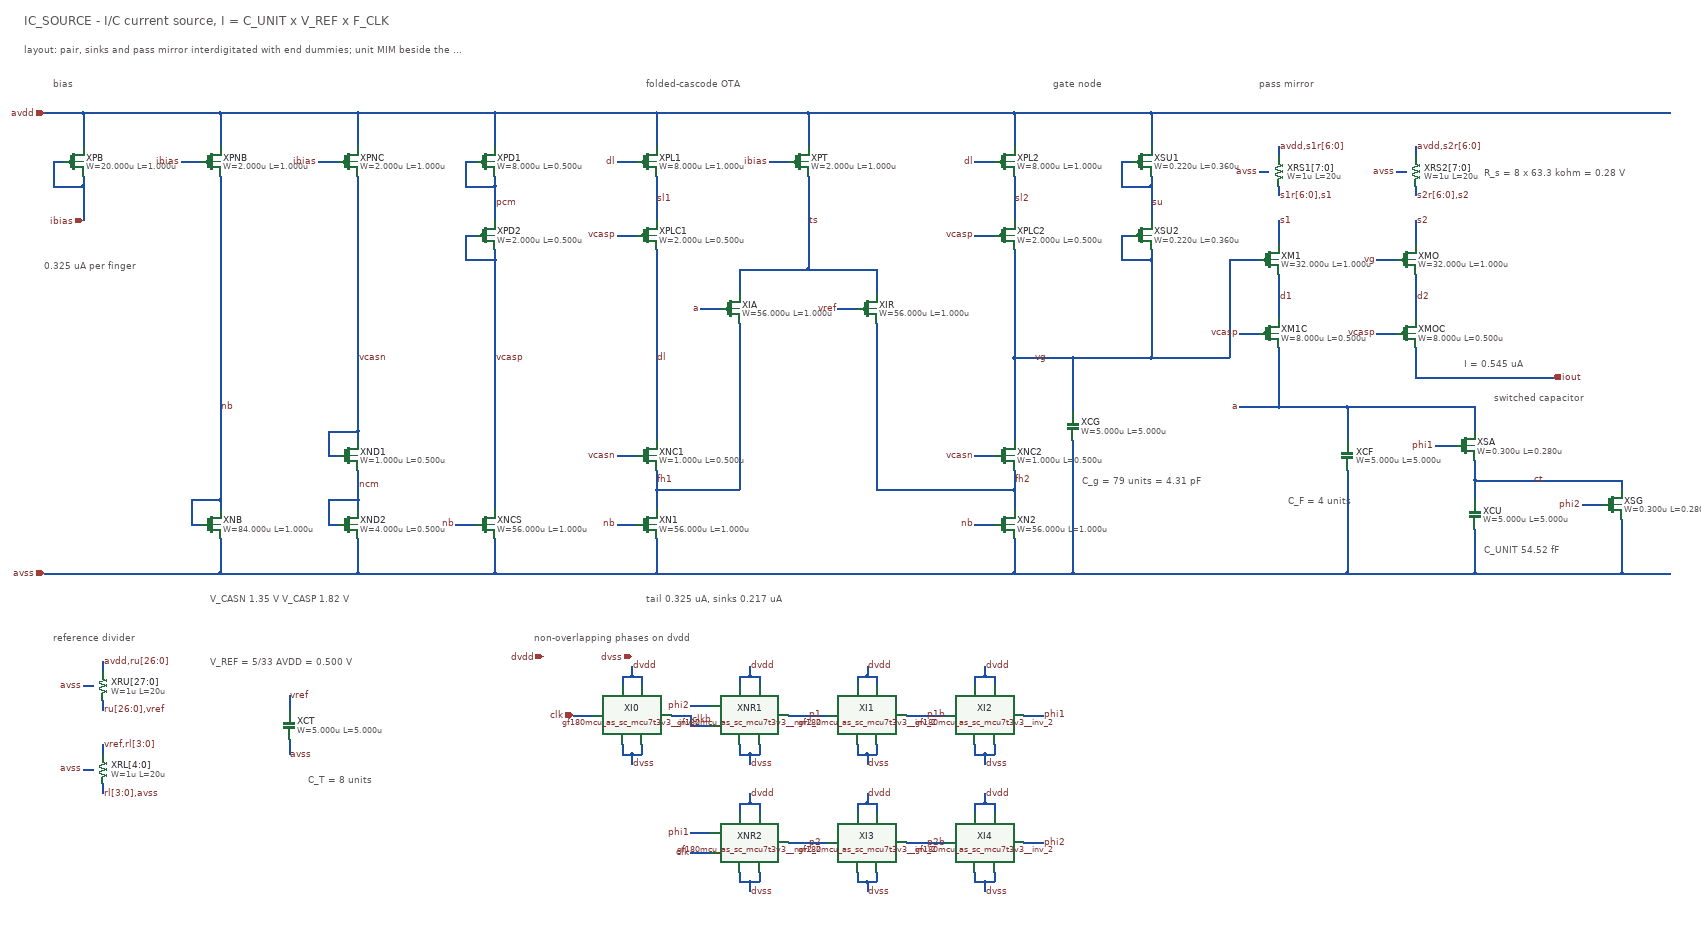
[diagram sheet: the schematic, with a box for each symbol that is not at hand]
v {xschem version=3.4.8RC file_version=1.2}
G {}
K {}
V {}
S {}
E {}
N 100 -1400 180 -1400 {}
N 100 -460 460 -460 {}
N 120 -1300 120 -1250 {}
N 120 -1300 140 -1300 {}
N 120 -1250 180 -1250 {}
N 180 -1400 180 -1330 {}
N 180 -1400 460 -1400 {}
N 180 -1270 180 -1250 {}
N 180 -1250 180 -1180 {}
N 180 -230 200 -230 {}
N 180 -60 200 -60 {}
N 220 -280 220 -260 {}
N 220 -200 220 -180 {}
N 220 -110 220 -90 {}
N 220 -30 220 -10 {}
N 380 -1300 420 -1300 {}
N 400 -610 400 -560 {}
N 400 -610 460 -610 {}
N 400 -560 420 -560 {}
N 460 -1400 460 -1330 {}
N 460 -1400 740 -1400 {}
N 460 -1270 460 -800 {}
N 460 -800 460 -610 {}
N 460 -610 460 -590 {}
N 460 -530 460 -460 {}
N 460 -460 740 -460 {}
N 600 -210 600 -180 {}
N 600 -120 600 -90 {}
N 660 -1300 700 -1300 {}
N 680 -750 680 -700 {}
N 680 -750 740 -750 {}
N 680 -700 700 -700 {}
N 680 -610 680 -560 {}
N 680 -610 740 -610 {}
N 680 -560 700 -560 {}
N 740 -1400 740 -1330 {}
N 740 -1400 1020 -1400 {}
N 740 -1270 740 -900 {}
N 740 -900 740 -750 {}
N 740 -750 740 -730 {}
N 740 -670 740 -640 {}
N 740 -640 740 -610 {}
N 740 -610 740 -590 {}
N 740 -530 740 -460 {}
N 740 -460 1020 -460 {}
N 940 -560 980 -560 {}
N 960 -1300 960 -1250 {}
N 960 -1300 980 -1300 {}
N 960 -1250 1020 -1250 {}
N 960 -1150 960 -1100 {}
N 960 -1150 980 -1150 {}
N 960 -1100 1020 -1100 {}
N 1020 -1400 1020 -1330 {}
N 1020 -1400 1350 -1400 {}
N 1020 -1270 1020 -1250 {}
N 1020 -1250 1020 -1215 {}
N 1020 -1215 1020 -1180 {}
N 1020 -1120 1020 -1100 {}
N 1020 -1100 1020 -900 {}
N 1020 -900 1020 -590 {}
N 1020 -530 1020 -460 {}
N 1020 -460 1350 -460 {}
N 1180 -170 1220 -170 {}
N 1270 -1300 1310 -1300 {}
N 1270 -1150 1310 -1150 {}
N 1270 -700 1310 -700 {}
N 1270 -560 1310 -560 {}
N 1280 -250 1280 -230 {}
N 1280 -250 1300 -250 {}
N 1280 -110 1280 -90 {}
N 1280 -90 1300 -90 {}
N 1300 -270 1300 -250 {}
N 1300 -250 1320 -250 {}
N 1300 -90 1300 -70 {}
N 1300 -90 1320 -90 {}
N 1320 -250 1320 -230 {}
N 1320 -110 1320 -90 {}
N 1350 -1400 1350 -1330 {}
N 1350 -1400 1660 -1400 {}
N 1350 -1270 1350 -1225 {}
N 1350 -1225 1350 -1180 {}
N 1350 -1120 1350 -900 {}
N 1350 -900 1350 -730 {}
N 1350 -670 1350 -650 {}
N 1350 -650 1350 -630 {}
N 1350 -630 1350 -590 {}
N 1350 -630 1520 -630 {}
N 1350 -530 1350 -460 {}
N 1350 -460 2080 -460 {}
N 1380 -170 1420 -170 {}
N 1420 -190 1460 -190 {}
N 1420 -170 1420 -160 {}
N 1420 -160 1420 -150 {}
N 1420 -150 1460 -150 {}
N 1420 70 1460 70 {}
N 1420 110 1460 110 {}
N 1440 -1000 1480 -1000 {}
N 1520 -1080 1520 -1030 {}
N 1520 -1080 1660 -1080 {}
N 1520 -970 1520 -630 {}
N 1520 -250 1520 -230 {}
N 1520 -250 1540 -250 {}
N 1520 -110 1520 -90 {}
N 1520 -90 1540 -90 {}
N 1520 10 1520 30 {}
N 1520 10 1540 10 {}
N 1520 150 1520 170 {}
N 1520 170 1540 170 {}
N 1540 -270 1540 -250 {}
N 1540 -250 1560 -250 {}
N 1540 -90 1540 -70 {}
N 1540 -90 1560 -90 {}
N 1540 -10 1540 10 {}
N 1540 10 1560 10 {}
N 1540 170 1540 190 {}
N 1540 170 1560 170 {}
N 1560 -250 1560 -230 {}
N 1560 -110 1560 -90 {}
N 1560 10 1560 30 {}
N 1560 150 1560 170 {}
N 1580 -1300 1620 -1300 {}
N 1620 -170 1660 -170 {}
N 1620 90 1660 90 {}
N 1660 -1400 1660 -1330 {}
N 1660 -1400 2080 -1400 {}
N 1660 -1270 1660 -1180 {}
N 1660 -1180 1660 -1080 {}
N 1660 -1080 1800 -1080 {}
N 1660 -170 1700 -170 {}
N 1660 90 1700 90 {}
N 1720 -1000 1760 -1000 {}
N 1760 -250 1760 -230 {}
N 1760 -250 1780 -250 {}
N 1760 -110 1760 -90 {}
N 1760 -90 1780 -90 {}
N 1760 10 1760 30 {}
N 1760 10 1780 10 {}
N 1760 150 1760 170 {}
N 1760 170 1780 170 {}
N 1780 -270 1780 -250 {}
N 1780 -250 1800 -250 {}
N 1780 -90 1780 -70 {}
N 1780 -90 1800 -90 {}
N 1780 -10 1780 10 {}
N 1780 10 1800 10 {}
N 1780 170 1780 190 {}
N 1780 170 1800 170 {}
N 1800 -1080 1800 -1030 {}
N 1800 -970 1800 -630 {}
N 1800 -630 2080 -630 {}
N 1800 -250 1800 -230 {}
N 1800 -110 1800 -90 {}
N 1800 10 1800 30 {}
N 1800 150 1800 170 {}
N 1860 -170 1900 -170 {}
N 1860 90 1900 90 {}
N 1900 -170 1940 -170 {}
N 1900 90 1940 90 {}
N 2000 -1300 2040 -1300 {}
N 2000 -1150 2040 -1150 {}
N 2000 -700 2040 -700 {}
N 2000 -560 2040 -560 {}
N 2000 -250 2000 -230 {}
N 2000 -250 2020 -250 {}
N 2000 -110 2000 -90 {}
N 2000 -90 2020 -90 {}
N 2000 10 2000 30 {}
N 2000 10 2020 10 {}
N 2000 150 2000 170 {}
N 2000 170 2020 170 {}
N 2020 -270 2020 -250 {}
N 2020 -250 2040 -250 {}
N 2020 -90 2020 -70 {}
N 2020 -90 2040 -90 {}
N 2020 -10 2020 10 {}
N 2020 10 2040 10 {}
N 2020 170 2020 190 {}
N 2020 170 2040 170 {}
N 2040 -250 2040 -230 {}
N 2040 -110 2040 -90 {}
N 2040 10 2040 30 {}
N 2040 150 2040 170 {}
N 2080 -1400 2080 -1330 {}
N 2080 -1400 2360 -1400 {}
N 2080 -1270 2080 -1225 {}
N 2080 -1225 2080 -1180 {}
N 2080 -1120 2080 -900 {}
N 2080 -900 2080 -730 {}
N 2080 -900 2120 -900 {}
N 2080 -670 2080 -650 {}
N 2080 -650 2080 -630 {}
N 2080 -630 2080 -590 {}
N 2080 -530 2080 -460 {}
N 2080 -460 2200 -460 {}
N 2100 -170 2140 -170 {}
N 2100 90 2140 90 {}
N 2120 -900 2200 -900 {}
N 2200 -900 2200 -790 {}
N 2200 -900 2360 -900 {}
N 2200 -730 2200 -460 {}
N 2200 -460 2760 -460 {}
N 2300 -1300 2300 -1250 {}
N 2300 -1300 2320 -1300 {}
N 2300 -1250 2360 -1250 {}
N 2300 -1150 2300 -1100 {}
N 2300 -1150 2320 -1150 {}
N 2300 -1100 2360 -1100 {}
N 2360 -1400 2360 -1330 {}
N 2360 -1400 3420 -1400 {}
N 2360 -1270 2360 -1250 {}
N 2360 -1250 2360 -1215 {}
N 2360 -1215 2360 -1180 {}
N 2360 -1120 2360 -1100 {}
N 2360 -1100 2360 -900 {}
N 2360 -900 2520 -900 {}
N 2520 -1100 2520 -900 {}
N 2520 -1100 2580 -1100 {}
N 2540 -950 2580 -950 {}
N 2540 -800 2620 -800 {}
N 2580 -1280 2600 -1280 {}
N 2620 -1330 2620 -1310 {}
N 2620 -1250 2620 -1230 {}
N 2620 -1180 2620 -1130 {}
N 2620 -1070 2620 -1025 {}
N 2620 -1025 2620 -980 {}
N 2620 -920 2620 -800 {}
N 2620 -800 2760 -800 {}
N 2760 -800 2760 -730 {}
N 2760 -800 3020 -800 {}
N 2760 -670 2760 -460 {}
N 2760 -460 3020 -460 {}
N 2820 -1100 2860 -1100 {}
N 2820 -950 2860 -950 {}
N 2860 -1280 2880 -1280 {}
N 2900 -1330 2900 -1310 {}
N 2900 -1250 2900 -1230 {}
N 2900 -1180 2900 -1130 {}
N 2900 -1070 2900 -1025 {}
N 2900 -1025 2900 -980 {}
N 2900 -920 2900 -860 {}
N 2900 -860 3180 -860 {}
N 2940 -720 2980 -720 {}
N 3020 -800 3020 -750 {}
N 3020 -690 3020 -650 {}
N 3020 -650 3020 -610 {}
N 3020 -650 3140 -650 {}
N 3020 -550 3020 -460 {}
N 3020 -460 3320 -460 {}
N 3140 -650 3320 -650 {}
N 3240 -600 3280 -600 {}
N 3320 -650 3320 -630 {}
N 3320 -570 3320 -460 {}
N 3320 -460 3420 -460 {}
T {IC_SOURCE  -  I/C current source, I = C_UNIT x V_REF x F_CLK} 60 -1600 0 0 0.75 0.75 {}
T {layout: pair, sinks and pass mirror interdigitated with end dummies; unit MIM beside the ramp's array; divider and R_s as unit-strip rows with dummies} 60 -1540 0 0 0.40 0.40 {}
T {bias} 120 -1470 0 0 0.45 0.45 {layer=13}
T {0.325 uA per finger} 100 -1100 0 0 0.35 0.35 {layer=4}
T {V_CASN 1.35 V   V_CASP 1.82 V} 440 -420 0 0 0.35 0.35 {layer=4}
T {folded-cascode OTA} 1330 -1470 0 0 0.45 0.45 {layer=13}
T {tail 0.325 uA, sinks 0.217 uA} 1330 -420 0 0 0.35 0.35 {layer=4}
T {gate node} 2160 -1470 0 0 0.45 0.45 {layer=13}
T {C_g = 79 units = 4.31 pF} 2220 -660 0 0 0.35 0.35 {layer=4}
T {pass mirror} 2580 -1470 0 0 0.45 0.45 {layer=13}
T {R_s = 8 x 63.3 kohm = 0.28 V} 3040 -1290 0 0 0.35 0.35 {layer=4}
T {I = 0.545 uA} 3000 -900 0 0 0.35 0.35 {layer=4}
T {switched capacitor} 3060 -830 0 0 0.45 0.45 {layer=13}
T {C_F = 4 units} 2640 -620 0 0 0.35 0.35 {layer=4}
T {C_UNIT 54.52 fF} 3040 -520 0 0 0.35 0.35 {layer=4}
T {reference divider} 120 -340 0 0 0.45 0.45 {layer=13}
T {V_REF = 5/33 AVDD = 0.500 V} 440 -290 0 0 0.35 0.35 {layer=4}
T {C_T = 8 units} 640 -50 0 0 0.35 0.35 {layer=4}
T {non-overlapping phases on dvdd} 1100 -340 0 0 0.45 0.45 {layer=13}
C {devices/iopin.sym} 100 -1400 0 0 {name=p_avdd lab=avdd sim_pinnumber=4}
C {devices/iopin.sym} 100 -460 0 0 {name=p_avss lab=avss sim_pinnumber=5}
C {symbols/pfet3_03v3.sym} 160 -1300 0 0 {name=XPB
L=1.000u
W=20.000u
nf=10
m=1
body=avdd
model=pfet_03v3
spiceprefix=""
format="@name @pinlist @body @model L=@L W=@W nf=@nf m=@m"}
C {devices/ipin.sym} 180 -1180 0 0 {name=p_ibias lab=ibias sim_pinnumber=2}
C {symbols/pfet3_03v3.sym} 440 -1300 0 0 {name=XPNB
L=1.000u
W=2.000u
nf=1
m=1
body=avdd
model=pfet_03v3
spiceprefix=""
format="@name @pinlist @body @model L=@L W=@W nf=@nf m=@m"}
C {devices/lab_pin.sym} 380 -1300 0 0 {name=l1 sig_type=std_logic lab=ibias}
C {symbols/nfet3_03v3.sym} 440 -560 0 0 {name=XNB
L=1.000u
W=84.000u
nf=42
m=1
body=avss
model=nfet_03v3
spiceprefix=""
format="@name @pinlist @body @model L=@L W=@W nf=@nf m=@m"}
C {devices/lab_pin.sym} 460 -800 0 1 {name=l2 sig_type=std_logic lab=nb}
C {symbols/pfet3_03v3.sym} 720 -1300 0 0 {name=XPNC
L=1.000u
W=2.000u
nf=1
m=1
body=avdd
model=pfet_03v3
spiceprefix=""
format="@name @pinlist @body @model L=@L W=@W nf=@nf m=@m"}
C {devices/lab_pin.sym} 660 -1300 0 0 {name=l3 sig_type=std_logic lab=ibias}
C {symbols/nfet3_03v3.sym} 720 -700 0 0 {name=XND1
L=0.500u
W=1.000u
nf=1
m=1
body=avss
model=nfet_03v3
spiceprefix=""
format="@name @pinlist @body @model L=@L W=@W nf=@nf m=@m"}
C {devices/lab_pin.sym} 740 -900 0 1 {name=l4 sig_type=std_logic lab=vcasn}
C {symbols/nfet3_03v3.sym} 720 -560 0 0 {name=XND2
L=0.500u
W=4.000u
nf=1
m=1
body=avss
model=nfet_03v3
spiceprefix=""
format="@name @pinlist @body @model L=@L W=@W nf=@nf m=@m"}
C {devices/lab_pin.sym} 740 -640 0 1 {name=l5 sig_type=std_logic lab=ncm}
C {symbols/pfet3_03v3.sym} 1000 -1300 0 0 {name=XPD1
L=0.500u
W=8.000u
nf=4
m=1
body=avdd
model=pfet_03v3
spiceprefix=""
format="@name @pinlist @body @model L=@L W=@W nf=@nf m=@m"}
C {symbols/pfet3_03v3.sym} 1000 -1150 0 0 {name=XPD2
L=0.500u
W=2.000u
nf=1
m=1
body=avdd
model=pfet_03v3
spiceprefix=""
format="@name @pinlist @body @model L=@L W=@W nf=@nf m=@m"}
C {devices/lab_pin.sym} 1020 -1215 0 1 {name=l6 sig_type=std_logic lab=pcm}
C {symbols/nfet3_03v3.sym} 1000 -560 0 0 {name=XNCS
L=1.000u
W=56.000u
nf=28
m=1
body=avss
model=nfet_03v3
spiceprefix=""
format="@name @pinlist @body @model L=@L W=@W nf=@nf m=@m"}
C {devices/lab_pin.sym} 940 -560 0 0 {name=l7 sig_type=std_logic lab=nb}
C {devices/lab_pin.sym} 1020 -900 0 1 {name=l8 sig_type=std_logic lab=vcasp}
C {symbols/pfet3_03v3.sym} 1330 -1300 0 0 {name=XPL1
L=1.000u
W=8.000u
nf=4
m=1
body=avdd
model=pfet_03v3
spiceprefix=""
format="@name @pinlist @body @model L=@L W=@W nf=@nf m=@m"}
C {devices/lab_pin.sym} 1270 -1300 0 0 {name=l9 sig_type=std_logic lab=dl}
C {symbols/pfet3_03v3.sym} 1330 -1150 0 0 {name=XPLC1
L=0.500u
W=2.000u
nf=1
m=1
body=avdd
model=pfet_03v3
spiceprefix=""
format="@name @pinlist @body @model L=@L W=@W nf=@nf m=@m"}
C {devices/lab_pin.sym} 1270 -1150 0 0 {name=l10 sig_type=std_logic lab=vcasp}
C {devices/lab_pin.sym} 1350 -1225 0 1 {name=l11 sig_type=std_logic lab=sl1}
C {symbols/nfet3_03v3.sym} 1330 -700 0 0 {name=XNC1
L=0.500u
W=1.000u
nf=1
m=1
body=avss
model=nfet_03v3
spiceprefix=""
format="@name @pinlist @body @model L=@L W=@W nf=@nf m=@m"}
C {devices/lab_pin.sym} 1270 -700 0 0 {name=l12 sig_type=std_logic lab=vcasn}
C {symbols/nfet3_03v3.sym} 1330 -560 0 0 {name=XN1
L=1.000u
W=56.000u
nf=28
m=1
body=avss
model=nfet_03v3
spiceprefix=""
format="@name @pinlist @body @model L=@L W=@W nf=@nf m=@m"}
C {devices/lab_pin.sym} 1270 -560 0 0 {name=l13 sig_type=std_logic lab=nb}
C {devices/lab_pin.sym} 1350 -650 0 1 {name=l14 sig_type=std_logic lab=fh1}
C {symbols/pfet3_03v3.sym} 2060 -1300 0 0 {name=XPL2
L=1.000u
W=8.000u
nf=4
m=1
body=avdd
model=pfet_03v3
spiceprefix=""
format="@name @pinlist @body @model L=@L W=@W nf=@nf m=@m"}
C {devices/lab_pin.sym} 2000 -1300 0 0 {name=l15 sig_type=std_logic lab=dl}
C {symbols/pfet3_03v3.sym} 2060 -1150 0 0 {name=XPLC2
L=0.500u
W=2.000u
nf=1
m=1
body=avdd
model=pfet_03v3
spiceprefix=""
format="@name @pinlist @body @model L=@L W=@W nf=@nf m=@m"}
C {devices/lab_pin.sym} 2000 -1150 0 0 {name=l16 sig_type=std_logic lab=vcasp}
C {devices/lab_pin.sym} 2080 -1225 0 1 {name=l17 sig_type=std_logic lab=sl2}
C {symbols/nfet3_03v3.sym} 2060 -700 0 0 {name=XNC2
L=0.500u
W=1.000u
nf=1
m=1
body=avss
model=nfet_03v3
spiceprefix=""
format="@name @pinlist @body @model L=@L W=@W nf=@nf m=@m"}
C {devices/lab_pin.sym} 2000 -700 0 0 {name=l18 sig_type=std_logic lab=vcasn}
C {symbols/nfet3_03v3.sym} 2060 -560 0 0 {name=XN2
L=1.000u
W=56.000u
nf=28
m=1
body=avss
model=nfet_03v3
spiceprefix=""
format="@name @pinlist @body @model L=@L W=@W nf=@nf m=@m"}
C {devices/lab_pin.sym} 2000 -560 0 0 {name=l19 sig_type=std_logic lab=nb}
C {devices/lab_pin.sym} 2080 -650 0 1 {name=l20 sig_type=std_logic lab=fh2}
C {devices/lab_pin.sym} 1350 -900 0 1 {name=l21 sig_type=std_logic lab=dl}
C {symbols/pfet3_03v3.sym} 1640 -1300 0 0 {name=XPT
L=1.000u
W=2.000u
nf=1
m=1
body=avdd
model=pfet_03v3
spiceprefix=""
format="@name @pinlist @body @model L=@L W=@W nf=@nf m=@m"}
C {devices/lab_pin.sym} 1580 -1300 0 0 {name=l22 sig_type=std_logic lab=ibias}
C {symbols/pfet3_03v3.sym} 1500 -1000 0 0 {name=XIA
L=1.000u
W=56.000u
nf=28
m=1
body=avdd
model=pfet_03v3
spiceprefix=""
format="@name @pinlist @body @model L=@L W=@W nf=@nf m=@m"}
C {devices/lab_pin.sym} 1440 -1000 0 0 {name=l23 sig_type=std_logic lab=a}
C {symbols/pfet3_03v3.sym} 1780 -1000 0 0 {name=XIR
L=1.000u
W=56.000u
nf=28
m=1
body=avdd
model=pfet_03v3
spiceprefix=""
format="@name @pinlist @body @model L=@L W=@W nf=@nf m=@m"}
C {devices/lab_pin.sym} 1720 -1000 0 0 {name=l24 sig_type=std_logic lab=vref}
C {devices/lab_pin.sym} 1660 -1180 0 1 {name=l25 sig_type=std_logic lab=ts}
C {devices/lab_pin.sym} 2120 -900 0 1 {name=l26 sig_type=std_logic lab=vg}
C {symbols/cap_mim_2f0fF.sym} 2200 -760 0 0 {name=XCG W=5.000u L=5.000u model=cap_mim_2f0_m4m5_noshield spiceprefix="" m=79}
C {symbols/pfet3_03v3.sym} 2340 -1300 0 0 {name=XSU1
L=0.360u
W=0.220u
nf=1
m=1
body=avdd
model=pfet_03v3
spiceprefix=""
format="@name @pinlist @body @model L=@L W=@W nf=@nf m=@m"}
C {symbols/pfet3_03v3.sym} 2340 -1150 0 0 {name=XSU2
L=0.360u
W=0.220u
nf=1
m=1
body=avdd
model=pfet_03v3
spiceprefix=""
format="@name @pinlist @body @model L=@L W=@W nf=@nf m=@m"}
C {devices/lab_pin.sym} 2360 -1215 0 1 {name=l27 sig_type=std_logic lab=su}
C {symbols/ppolyf_u_3k.sym} 2620 -1280 0 0 {name=XRS1[7:0]
W=1u
L=20u
model=ppolyf_u_3k
spiceprefix=""
m=1}
C {devices/lab_pin.sym} 2620 -1330 0 1 {name=l28 sig_type=std_logic lab=avdd,s1r[6:0]}
C {devices/lab_pin.sym} 2620 -1230 0 1 {name=l29 sig_type=std_logic lab=s1r[6:0],s1}
C {devices/lab_pin.sym} 2580 -1280 0 0 {name=l30 sig_type=std_logic lab=avss}
C {symbols/pfet3_03v3.sym} 2600 -1100 0 0 {name=XM1
L=1.000u
W=32.000u
nf=16
m=1
body=avdd
model=pfet_03v3
spiceprefix=""
format="@name @pinlist @body @model L=@L W=@W nf=@nf m=@m"}
C {devices/lab_pin.sym} 2620 -1180 0 1 {name=l31 sig_type=std_logic lab=s1}
C {symbols/pfet3_03v3.sym} 2600 -950 0 0 {name=XM1C
L=0.500u
W=8.000u
nf=4
m=1
body=avdd
model=pfet_03v3
spiceprefix=""
format="@name @pinlist @body @model L=@L W=@W nf=@nf m=@m"}
C {devices/lab_pin.sym} 2540 -950 0 0 {name=l32 sig_type=std_logic lab=vcasp}
C {devices/lab_pin.sym} 2620 -1025 0 1 {name=l33 sig_type=std_logic lab=d1}
C {symbols/ppolyf_u_3k.sym} 2900 -1280 0 0 {name=XRS2[7:0]
W=1u
L=20u
model=ppolyf_u_3k
spiceprefix=""
m=1}
C {devices/lab_pin.sym} 2900 -1330 0 1 {name=l34 sig_type=std_logic lab=avdd,s2r[6:0]}
C {devices/lab_pin.sym} 2900 -1230 0 1 {name=l35 sig_type=std_logic lab=s2r[6:0],s2}
C {devices/lab_pin.sym} 2860 -1280 0 0 {name=l36 sig_type=std_logic lab=avss}
C {symbols/pfet3_03v3.sym} 2880 -1100 0 0 {name=XMO
L=1.000u
W=32.000u
nf=16
m=1
body=avdd
model=pfet_03v3
spiceprefix=""
format="@name @pinlist @body @model L=@L W=@W nf=@nf m=@m"}
C {devices/lab_pin.sym} 2820 -1100 0 0 {name=l37 sig_type=std_logic lab=vg}
C {devices/lab_pin.sym} 2900 -1180 0 1 {name=l38 sig_type=std_logic lab=s2}
C {symbols/pfet3_03v3.sym} 2880 -950 0 0 {name=XMOC
L=0.500u
W=8.000u
nf=4
m=1
body=avdd
model=pfet_03v3
spiceprefix=""
format="@name @pinlist @body @model L=@L W=@W nf=@nf m=@m"}
C {devices/lab_pin.sym} 2820 -950 0 0 {name=l39 sig_type=std_logic lab=vcasp}
C {devices/lab_pin.sym} 2900 -1025 0 1 {name=l40 sig_type=std_logic lab=d2}
C {devices/opin.sym} 3180 -860 0 0 {name=p_iout lab=iout sim_pinnumber=1}
C {devices/lab_pin.sym} 2540 -800 0 0 {name=l41 sig_type=std_logic lab=a}
C {symbols/cap_mim_2f0fF.sym} 2760 -700 0 0 {name=XCF W=5.000u L=5.000u model=cap_mim_2f0_m4m5_noshield spiceprefix="" m=4}
C {symbols/nfet3_03v3.sym} 3000 -720 0 0 {name=XSA
L=0.280u
W=0.300u
nf=1
m=1
body=avss
model=nfet_03v3
spiceprefix=""
format="@name @pinlist @body @model L=@L W=@W nf=@nf m=@m"}
C {devices/lab_pin.sym} 2940 -720 0 0 {name=l42 sig_type=std_logic lab=phi1}
C {symbols/cap_mim_2f0fF.sym} 3020 -580 0 0 {name=XCU W=5.000u L=5.000u model=cap_mim_2f0_m4m5_noshield spiceprefix="" m=1}
C {symbols/nfet3_03v3.sym} 3300 -600 0 0 {name=XSG
L=0.280u
W=0.300u
nf=1
m=1
body=avss
model=nfet_03v3
spiceprefix=""
format="@name @pinlist @body @model L=@L W=@W nf=@nf m=@m"}
C {devices/lab_pin.sym} 3240 -600 0 0 {name=l43 sig_type=std_logic lab=phi2}
C {devices/lab_pin.sym} 3140 -650 0 1 {name=l44 sig_type=std_logic lab=ct}
C {symbols/ppolyf_u_3k.sym} 220 -230 0 0 {name=XRU[27:0]
W=1u
L=20u
model=ppolyf_u_3k
spiceprefix=""
m=1}
C {devices/lab_pin.sym} 220 -280 0 1 {name=l45 sig_type=std_logic lab=avdd,ru[26:0]}
C {devices/lab_pin.sym} 220 -180 0 1 {name=l46 sig_type=std_logic lab=ru[26:0],vref}
C {devices/lab_pin.sym} 180 -230 0 0 {name=l47 sig_type=std_logic lab=avss}
C {symbols/ppolyf_u_3k.sym} 220 -60 0 0 {name=XRL[4:0]
W=1u
L=20u
model=ppolyf_u_3k
spiceprefix=""
m=1}
C {devices/lab_pin.sym} 220 -110 0 1 {name=l48 sig_type=std_logic lab=vref,rl[3:0]}
C {devices/lab_pin.sym} 220 -10 0 1 {name=l49 sig_type=std_logic lab=rl[3:0],avss}
C {devices/lab_pin.sym} 180 -60 0 0 {name=l50 sig_type=std_logic lab=avss}
C {symbols/cap_mim_2f0fF.sym} 600 -150 0 0 {name=XCT W=5.000u L=5.000u model=cap_mim_2f0_m4m5_noshield spiceprefix="" m=8}
C {devices/lab_pin.sym} 600 -210 0 1 {name=l51 sig_type=std_logic lab=vref}
C {devices/lab_pin.sym} 600 -90 0 1 {name=l52 sig_type=std_logic lab=avss}
C {devices/iopin.sym} 1120 -290 0 0 {name=p_dvdd lab=dvdd sim_pinnumber=6}
C {devices/iopin.sym} 1300 -290 0 0 {name=p_dvss lab=dvss sim_pinnumber=7}
C {gf180mcu_as_sc_mcu7t3v3__inv_2.sym} 1300 -170 0 0 {name=XI0}
C {devices/lab_pin.sym} 1300 -270 0 1 {name=l53 sig_type=std_logic lab=dvdd}
C {devices/lab_pin.sym} 1300 -70 0 1 {name=l54 sig_type=std_logic lab=dvss}
C {devices/ipin.sym} 1180 -170 0 0 {name=p_clk lab=clk sim_pinnumber=3}
C {gf180mcu_as_sc_mcu7t3v3__nor2_2.sym} 1540 -170 0 0 {name=XNR1}
C {devices/lab_pin.sym} 1540 -270 0 1 {name=l55 sig_type=std_logic lab=dvdd}
C {devices/lab_pin.sym} 1540 -70 0 1 {name=l56 sig_type=std_logic lab=dvss}
C {devices/lab_pin.sym} 1420 -160 0 1 {name=l57 sig_type=std_logic lab=clkb}
C {devices/lab_pin.sym} 1420 -190 0 0 {name=l58 sig_type=std_logic lab=phi2}
C {gf180mcu_as_sc_mcu7t3v3__inv_2.sym} 1780 -170 0 0 {name=XI1}
C {devices/lab_pin.sym} 1780 -270 0 1 {name=l59 sig_type=std_logic lab=dvdd}
C {devices/lab_pin.sym} 1780 -70 0 1 {name=l60 sig_type=std_logic lab=dvss}
C {devices/lab_pin.sym} 1660 -170 0 1 {name=l61 sig_type=std_logic lab=p1}
C {gf180mcu_as_sc_mcu7t3v3__inv_2.sym} 2020 -170 0 0 {name=XI2}
C {devices/lab_pin.sym} 2020 -270 0 1 {name=l62 sig_type=std_logic lab=dvdd}
C {devices/lab_pin.sym} 2020 -70 0 1 {name=l63 sig_type=std_logic lab=dvss}
C {devices/lab_pin.sym} 1900 -170 0 1 {name=l64 sig_type=std_logic lab=p1b}
C {devices/lab_pin.sym} 2140 -170 0 1 {name=l65 sig_type=std_logic lab=phi1}
C {gf180mcu_as_sc_mcu7t3v3__nor2_2.sym} 1540 90 0 0 {name=XNR2}
C {devices/lab_pin.sym} 1540 -10 0 1 {name=l66 sig_type=std_logic lab=dvdd}
C {devices/lab_pin.sym} 1540 190 0 1 {name=l67 sig_type=std_logic lab=dvss}
C {devices/lab_pin.sym} 1420 110 0 0 {name=l68 sig_type=std_logic lab=clk}
C {devices/lab_pin.sym} 1420 70 0 0 {name=l69 sig_type=std_logic lab=phi1}
C {gf180mcu_as_sc_mcu7t3v3__inv_2.sym} 1780 90 0 0 {name=XI3}
C {devices/lab_pin.sym} 1780 -10 0 1 {name=l70 sig_type=std_logic lab=dvdd}
C {devices/lab_pin.sym} 1780 190 0 1 {name=l71 sig_type=std_logic lab=dvss}
C {devices/lab_pin.sym} 1660 90 0 1 {name=l72 sig_type=std_logic lab=p2}
C {gf180mcu_as_sc_mcu7t3v3__inv_2.sym} 2020 90 0 0 {name=XI4}
C {devices/lab_pin.sym} 2020 -10 0 1 {name=l73 sig_type=std_logic lab=dvdd}
C {devices/lab_pin.sym} 2020 190 0 1 {name=l74 sig_type=std_logic lab=dvss}
C {devices/lab_pin.sym} 1900 90 0 1 {name=l75 sig_type=std_logic lab=p2b}
C {devices/lab_pin.sym} 2140 90 0 1 {name=l76 sig_type=std_logic lab=phi2}
